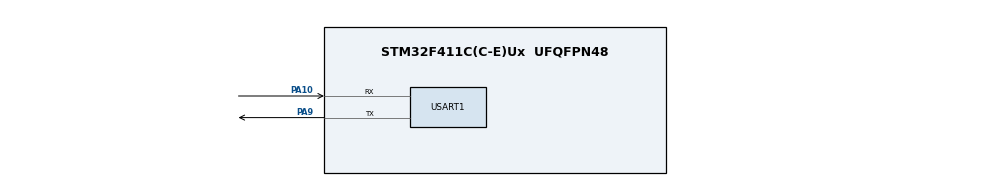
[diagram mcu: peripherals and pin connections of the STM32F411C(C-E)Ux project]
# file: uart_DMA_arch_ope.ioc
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Dma.Request0=USART1_RX
Dma.USART1_RX.0.Direction=DMA_PERIPH_TO_MEMORY
Dma.USART1_RX.0.FIFOMode=DMA_FIFOMODE_DISABLE
Dma.USART1_RX.0.Instance=DMA2_Stream2
Dma.USART1_RX.0.MemDataAlignment=DMA_MDATAALIGN_WORD
Dma.USART1_RX.0.MemInc=DMA_MINC_ENABLE
Dma.USART1_RX.0.Mode=DMA_NORMAL
Dma.USART1_RX.0.PeriphDataAlignment=DMA_PDATAALIGN_WORD
Dma.USART1_RX.0.PeriphInc=DMA_PINC_DISABLE
Dma.USART1_RX.0.Priority=DMA_PRIORITY_LOW
FREERTOS.Tasks01=defaultTask,24,128,StartDefaultTask,Default,NULL,Dynamic,NULL,NULL
Mcu.Family=STM32F4
Mcu.Name=STM32F411C(C-E)Ux
Mcu.Package=UFQFPN48
NVIC.DMA2_Stream2_IRQn=true\:5\:0\:false\:false\:true\:true\:false\:true\:true
NVIC.PriorityGroup=NVIC_PRIORITYGROUP_4
NVIC.TIM2_IRQn=true\:15\:0\:false\:false\:true\:false\:false\:true\:true
NVIC.TimeBase=TIM2_IRQn
NVIC.TimeBaseIP=TIM2
NVIC.USART1_IRQn=true\:5\:0\:false\:false\:true\:true\:true\:true\:true
PA10.Mode=Asynchronous
PA10.Signal=USART1_RX
PA9.Mode=Asynchronous
PA9.Signal=USART1_TX
ProjectManager.HeapSize=0x200
ProjectManager.StackSize=0x400
ProjectManager.TargetToolchain=MDK-ARM V5.32
RCC.AHBFreq_Value=16000000
RCC.APB1Freq_Value=16000000
RCC.APB1TimFreq_Value=16000000
RCC.APB2Freq_Value=16000000
RCC.APB2TimFreq_Value=16000000
RCC.CortexFreq_Value=16000000
RCC.HCLKFreq_Value=16000000
RCC.HSE_VALUE=25000000
RCC.HSI_VALUE=16000000
RCC.LSE_VALUE=32768
RCC.SYSCLKFreq_VALUE=16000000
RCC.VCOOutputFreq_Value=192000000
USART1.VirtualMode=VM_ASYNC
VP_FREERTOS_VS_CMSIS_V2.Mode=CMSIS_V2
VP_SYS_VS_tim2.Mode=TIM2
board=custom

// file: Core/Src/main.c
/* USER CODE BEGIN Header */
/**
 ******************************************************************************
 * @file           : main.c
 * @brief          : Main program body
 ******************************************************************************
 * @attention
 *
 * Copyright (c) 2026 STMicroelectronics.
 * All rights reserved.
 *
 * This software is licensed under terms that can be found in the LICENSE file
 * in the root directory of this software component.
 * If no LICENSE file comes with this software, it is provided AS-IS.
 *
 ******************************************************************************
 */
/* USER CODE END Header */
#include "main.h"
#include "cmsis_os.h"
#include "dma.h"
#include "usart.h"
#include "gpio.h"

/* USER CODE BEGIN Includes */
#include <stdlib.h>
#include "elog.h"
/* USER CODE END Includes */

void SystemClock_Config(void);
void MX_FREERTOS_Init(void);

int main(void)
{

  /* MCU Configuration--------------------------------------------------------*/

  /* Reset of all peripherals, Initializes the Flash interface and the Systick. */
  HAL_Init();

  /* USER CODE BEGIN Init */
  elog_init();
  elog_start();
  elog_set_fmt(ELOG_LVL_ASSERT, ELOG_FMT_ALL);
  elog_set_fmt(ELOG_LVL_ERROR, ELOG_FMT_LVL);
  elog_set_fmt(ELOG_LVL_WARN, ELOG_FMT_LVL);
  elog_set_fmt(ELOG_LVL_INFO, ELOG_FMT_LVL);
  elog_set_fmt(ELOG_LVL_DEBUG, ELOG_FMT_ALL);
  elog_set_fmt(ELOG_LVL_VERBOSE, ELOG_FMT_ALL);
  /* USER CODE END Init */

  /* Configure the system clock */
  SystemClock_Config();

  /* Initialize all configured peripherals */
  MX_GPIO_Init();
  MX_DMA_Init();
  MX_USART1_UART_Init();

  /* Init scheduler */
  osKernelInitialize(); /* Call init function for freertos objects (in freertos.c) */
  MX_FREERTOS_Init();

  /* Start scheduler */
  osKernelStart();
  /* We should never get here as control is now taken by the scheduler */
  /* Infinite loop */
  while (1)
  {

  }
}

void SystemClock_Config(void)
{
  RCC_OscInitTypeDef RCC_OscInitStruct = {0};
  RCC_ClkInitTypeDef RCC_ClkInitStruct = {0};

  /** Configure the main internal regulator output voltage
   */
  __HAL_RCC_PWR_CLK_ENABLE();
  __HAL_PWR_VOLTAGESCALING_CONFIG(PWR_REGULATOR_VOLTAGE_SCALE1);

  /** Initializes the RCC Oscillators according to the specified parameters
   * in the RCC_OscInitTypeDef structure.
   */
  RCC_OscInitStruct.OscillatorType = RCC_OSCILLATORTYPE_HSI;
  RCC_OscInitStruct.HSIState = RCC_HSI_ON;
    RCC_OscInitStruct.PLL.PLLState = RCC_PLL_ON;
    RCC_OscInitStruct.PLL.PLLSource = RCC_PLLSOURCE_HSE;
    RCC_OscInitStruct.PLL.PLLM = 12;
    RCC_OscInitStruct.PLL.PLLN = 96;
    RCC_OscInitStruct.PLL.PLLP = RCC_PLLP_DIV2;
    RCC_OscInitStruct.PLL.PLLQ = 4;
  if (HAL_RCC_OscConfig(&RCC_OscInitStruct) != HAL_OK)
  {
    Error_Handler();
  }

  /** Initializes the CPU, AHB and APB buses clocks
   */
  RCC_ClkInitStruct.ClockType = RCC_CLOCKTYPE_HCLK | RCC_CLOCKTYPE_SYSCLK | RCC_CLOCKTYPE_PCLK1 | RCC_CLOCKTYPE_PCLK2;
  RCC_ClkInitStruct.SYSCLKSource = RCC_SYSCLKSOURCE_PLLCLK;
  RCC_ClkInitStruct.AHBCLKDivider = RCC_SYSCLK_DIV1;
  RCC_ClkInitStruct.APB1CLKDivider = RCC_HCLK_DIV2;
  RCC_ClkInitStruct.APB2CLKDivider = RCC_HCLK_DIV1;

  if (HAL_RCC_ClockConfig(&RCC_ClkInitStruct, FLASH_LATENCY_3) != HAL_OK)
  {
    Error_Handler();
  }
}

void HAL_TIM_PeriodElapsedCallback(TIM_HandleTypeDef *htim)
{
  if (htim->Instance == TIM2)
  {
    HAL_IncTick();
  }
}

void Error_Handler(void)
{
  __disable_irq();
  while (1)
  {
  }
}

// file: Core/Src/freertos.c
/* USER CODE BEGIN Header */
/**
 ******************************************************************************
 * File Name          : freertos.c
 * Description        : Code for freertos applications
 ******************************************************************************
 * @attention
 *
 * Copyright (c) 2026 STMicroelectronics.
 * All rights reserved.
 *
 * This software is licensed under terms that can be found in the LICENSE file
 * in the root directory of this software component.
 * If no LICENSE file comes with this software, it is provided AS-IS.
 *
 ******************************************************************************
 */
/* USER CODE END Header */

#include "FreeRTOS.h"
#include "task.h"
#include "main.h"
#include "cmsis_os.h"

/* USER CODE BEGIN Includes */
#include "elog.h"
#include "ring_buffer.h"
#include "proto.h"
#include "queue.h"
/* USER CODE END Includes */

/* USER CODE BEGIN PD */
extern UART_HandleTypeDef huart1;
static ring_buffer_t g_ring_buffer;
extern  app_subscribe_t app_subscribers[MAX_SUBSCRIBERS]; // 订阅者

QueueHandle_t xrecvque;      /* ISR → 前端 */
QueueHandle_t xqueue_notify; /* 前端 → 后端 */

/* USER CODE END PD */

/* Definitions for defaultTask */
osThreadId_t defaultTaskHandle;
const osThreadAttr_t defaultTask_attributes = {
    .name = "defaultTask",
    .stack_size = 128 * 4,
    .priority = (osPriority_t)osPriorityNormal,
};

osThreadId_t TaskAHandle;
const osThreadAttr_t TaskA_attributes = {
    .name = "TaskA",
    .stack_size = 128 * 8,
    .priority = (osPriority_t)osPriorityNormal,
};

osThreadId_t TaskBHandle;
const osThreadAttr_t TaskB_attributes = {
    .name = "TaskB",
    .stack_size = 128 * 8,
    .priority = (osPriority_t)osPriorityNormal,
};

void StartDefaultTask(void *argument);
void TaskA(void *argument);
void TaskB(void *argument);

void MX_FREERTOS_Init(void); /* (MISRA C 2004 rule 8.1) */

void MX_FREERTOS_Init(void)
{
  /* USER CODE BEGIN Init */
  // Initialize ring buffer
  ring_buffer_init(&g_ring_buffer);

  // Initialize queue
  xrecvque = xQueueCreate(1, sizeof(uint32_t));
  xqueue_notify = xQueueCreate(1, sizeof(uint32_t));
  /* USER CODE END Init */

  /* Create the thread(s) */
  /* creation of defaultTask */
  defaultTaskHandle = osThreadNew(StartDefaultTask, NULL, &defaultTask_attributes);
  TaskAHandle = osThreadNew(TaskA, NULL, &TaskA_attributes);
  TaskBHandle = osThreadNew(TaskB, NULL, &TaskB_attributes);

}

void StartDefaultTask(void *argument)
{
  /* USER CODE BEGIN StartDefaultTask */
  /* Infinite loop */
  // app 订阅数据
  QueueHandle_t rx_queue1 = xQueueCreate(10, sizeof(app_msg_t));

  app_subscribe_t app1 = {.cmd = {0x01}, .rx_queue = rx_queue1};
  app_subscribers[0] = app1; // 注册到全局订阅表

  app_msg_t app1_msg = {0};
  for (;;)
  {
    if (xQueueReceive(rx_queue1, &app1_msg, portMAX_DELAY))
    {
      // 处理数据
      log_i("app1_msg_cnt: %d", app1_msg.data_cnt);
      for (int i = 0; i < app1_msg.data_cnt; i++)
      {
        log_i("app1_msg_data: %d", app1_msg.data[i]);
      }
    }
    osDelay(1);
  }
  /* USER CODE END StartDefaultTask */
}

/* USER CODE BEGIN Application */

/* ─── 前端 Task：串口驱动层 ─── */
void TaskA(void *argument)
{
  log_i("TaskA started !!!");

  uint32_t irq_signal;
  /* ① 启动串口接收 */
  // 单字节接收
  //   HAL_UART_Receive_DMA(&huart1, uart1_rx_buf, 1);

  // 多字节接收
  HAL_UARTEx_ReceiveToIdle_DMA(&huart1, g_ring_buffer.data, RING_BUF_SIZE);

  for (;;)
  {
    if (xQueueReceive(xrecvque, &irq_signal, portMAX_DELAY) == pdPASS)
    {
      if (IRQ_SEND_TO_THREAD == irq_signal)
      {
        if (ring_buffer_is_full(&g_ring_buffer))
        {
          log_i("Buffer full, skip notify!");
          continue;
        }

        uint32_t notify = FRONT_SEND_TO_END;
        xQueueSend(xqueue_notify, &notify, 0);
      }
    }
  }
}

/* ─── 后端 Task：应用协议层 ─── */
void TaskB(void *argument)
{
  log_i("TaskB started !!!");

  uint32_t app_signal;
  for (;;)
  {
    if (xQueueReceive(xqueue_notify, &app_signal, portMAX_DELAY) == pdPASS)
    {
      if (FRONT_SEND_TO_END == app_signal)
      {
        /* 对数据进行解包：检测包头 → 输出 → 检测包尾 → 停止 */
        frame_parse_transfer(&g_ring_buffer);
      }
    }
  }
}

/* USER CODE END Application */

void dma_rx_half_irq_callback(UART_HandleTypeDef *huart, uint16_t Size)
{
  if (huart->Instance == USART1)
  {
    BaseType_t xHigherPriorityTaskWoken = pdFALSE;
    size_t head_pos = 0;
    uint8_t ret = 0xfe;

    ret = ring_buffer_get_head(&g_ring_buffer, &head_pos);
    if (ret != 0)
    {
      log_i("ring_buffer_get_head error: %d", ret);
    }

    uint32_t half_size = RING_BUF_SIZE / 2;
    uint32_t move_pos = half_size - (head_pos % half_size);

    ring_buffer_move_head(&g_ring_buffer, move_pos);

    /* ② 通知前端 */
    uint32_t notify = IRQ_SEND_TO_THREAD;
    xQueueSendFromISR(xrecvque, &notify, &xHigherPriorityTaskWoken);

    portYIELD_FROM_ISR(xHigherPriorityTaskWoken);
  }
}

void dma_rx_complete_irq_callback(UART_HandleTypeDef *huart, uint16_t Size)
{
  if (huart->Instance == USART1)
  {
    BaseType_t xHigherPriorityTaskWoken = pdFALSE;
    log_i("dma_rx_irq_callback size:%d", Size);
    size_t head_pos = 0;
    uint8_t ret = 0xfe;

    ret = ring_buffer_get_head(&g_ring_buffer, &head_pos);
    if (ret != 0)
    {
      log_i("ring_buffer_get_head error: %d", ret);
    }
    uint32_t move_pos = RING_BUF_SIZE - (head_pos % RING_BUF_SIZE);
    log_i("move_pos:%d", move_pos);
    ring_buffer_move_head(&g_ring_buffer, move_pos);
    log_i("ring_buffer_move_head done, head_pos:%d", g_ring_buffer.head);

    /* ② 通知前端 */
    uint32_t notify = IRQ_SEND_TO_THREAD;
    xQueueSendFromISR(xrecvque, &notify, &xHigherPriorityTaskWoken);

    portYIELD_FROM_ISR(xHigherPriorityTaskWoken);
  }
}

void uart_idle_irq_callback(UART_HandleTypeDef *huart, uint16_t Size)
{
  if (huart->Instance == USART1)
  {
    BaseType_t xHigherPriorityTaskWoken = pdFALSE;
    log_i("uart_idle_irq_callback, size:%d", Size);
    size_t head_pos = 0;
    uint8_t ret = 0xfe;
    uint32_t move_pos = 0;

    ret = ring_buffer_get_head(&g_ring_buffer, &head_pos);
    if (ret != 0)
    {
      log_i("ring_buffer_get_head error: %d", ret);
    }
    if (Size < head_pos)
    {
      move_pos = (Size + RING_BUF_SIZE) - (head_pos % RING_BUF_SIZE);
    }
    else
    {
      move_pos = Size - (head_pos % RING_BUF_SIZE);
    }

    log_i("move_pos:%d", move_pos);
    ring_buffer_move_head(&g_ring_buffer, move_pos);
    log_i("ring_buffer_move_head done, head_pos:%d", g_ring_buffer.head);

    /* ② 通知前端 */
    uint32_t notify = IRQ_SEND_TO_THREAD;
    xQueueSendFromISR(xrecvque, &notify, &xHigherPriorityTaskWoken);

    portYIELD_FROM_ISR(xHigherPriorityTaskWoken);
  }
}
